VERSION 5.7 ;
  NOWIREEXTENSIONATPIN ON ;
  DIVIDERCHAR "/" ;
  BUSBITCHARS "[]" ;
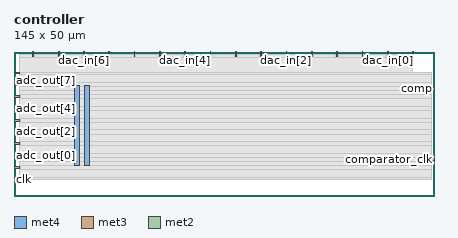
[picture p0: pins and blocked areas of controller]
MACRO controller
  CLASS BLOCK ;
  FOREIGN controller ;
  ORIGIN 0.000 0.000 ;
  SIZE 145.000 BY 50.000 ;
  PIN GND
    DIRECTION INOUT ;
    USE GROUND ;
    PORT
      LAYER met4 ;
        RECT 24.340 10.640 25.940 38.320 ;
    END
  END GND
  PIN VDD
    DIRECTION INOUT ;
    USE POWER ;
    PORT
      LAYER met4 ;
        RECT 21.040 10.640 22.640 38.320 ;
    END
  END VDD
  PIN adc_out[0]
    DIRECTION OUTPUT ;
    USE SIGNAL ;
    ANTENNADIFFAREA 0.445500 ;
    PORT
      LAYER met3 ;
        RECT 0.000 13.640 2.000 14.240 ;
    END
  END adc_out[0]
  PIN adc_out[1]
    DIRECTION OUTPUT ;
    USE SIGNAL ;
    ANTENNADIFFAREA 0.445500 ;
    PORT
      LAYER met3 ;
        RECT 0.000 17.720 2.000 18.320 ;
    END
  END adc_out[1]
  PIN adc_out[2]
    DIRECTION OUTPUT ;
    USE SIGNAL ;
    ANTENNADIFFAREA 0.445500 ;
    PORT
      LAYER met3 ;
        RECT 0.000 21.800 2.000 22.400 ;
    END
  END adc_out[2]
  PIN adc_out[3]
    DIRECTION OUTPUT ;
    USE SIGNAL ;
    ANTENNADIFFAREA 0.445500 ;
    PORT
      LAYER met3 ;
        RECT 0.000 25.880 2.000 26.480 ;
    END
  END adc_out[3]
  PIN adc_out[4]
    DIRECTION OUTPUT ;
    USE SIGNAL ;
    ANTENNADIFFAREA 0.445500 ;
    PORT
      LAYER met3 ;
        RECT 0.000 29.960 2.000 30.560 ;
    END
  END adc_out[4]
  PIN adc_out[5]
    DIRECTION OUTPUT ;
    USE SIGNAL ;
    ANTENNADIFFAREA 0.445500 ;
    PORT
      LAYER met3 ;
        RECT 0.000 34.040 2.000 34.640 ;
    END
  END adc_out[5]
  PIN adc_out[6]
    DIRECTION OUTPUT ;
    USE SIGNAL ;
    ANTENNADIFFAREA 0.445500 ;
    PORT
      LAYER met3 ;
        RECT 0.000 38.120 2.000 38.720 ;
    END
  END adc_out[6]
  PIN adc_out[7]
    DIRECTION OUTPUT ;
    USE SIGNAL ;
    ANTENNADIFFAREA 0.445500 ;
    PORT
      LAYER met3 ;
        RECT 0.000 42.200 2.000 42.800 ;
    END
  END adc_out[7]
  PIN clk
    DIRECTION INPUT ;
    USE SIGNAL ;
    ANTENNAGATEAREA 0.852000 ;
    PORT
      LAYER met3 ;
        RECT 0.000 5.480 2.000 6.080 ;
    END
  END clk
  PIN comp
    DIRECTION INPUT ;
    USE SIGNAL ;
    ANTENNAGATEAREA 0.196500 ;
    PORT
      LAYER met3 ;
        RECT 143.000 36.760 145.000 37.360 ;
    END
  END comp
  PIN comparator_clk
    DIRECTION OUTPUT ;
    USE SIGNAL ;
    ANTENNADIFFAREA 0.445500 ;
    PORT
      LAYER met3 ;
        RECT 143.000 12.280 145.000 12.880 ;
    END
  END comparator_clk
  PIN dac_in[0]
    DIRECTION OUTPUT ;
    USE SIGNAL ;
    ANTENNADIFFAREA 0.445500 ;
    PORT
      LAYER met2 ;
        RECT 128.890 48.000 129.170 50.000 ;
    END
  END dac_in[0]
  PIN dac_in[1]
    DIRECTION OUTPUT ;
    USE SIGNAL ;
    ANTENNADIFFAREA 0.445500 ;
    PORT
      LAYER met2 ;
        RECT 111.410 48.000 111.690 50.000 ;
    END
  END dac_in[1]
  PIN dac_in[2]
    DIRECTION OUTPUT ;
    USE SIGNAL ;
    ANTENNADIFFAREA 0.445500 ;
    PORT
      LAYER met2 ;
        RECT 93.930 48.000 94.210 50.000 ;
    END
  END dac_in[2]
  PIN dac_in[3]
    DIRECTION OUTPUT ;
    USE SIGNAL ;
    ANTENNADIFFAREA 0.445500 ;
    PORT
      LAYER met2 ;
        RECT 76.450 48.000 76.730 50.000 ;
    END
  END dac_in[3]
  PIN dac_in[4]
    DIRECTION OUTPUT ;
    USE SIGNAL ;
    ANTENNADIFFAREA 0.445500 ;
    PORT
      LAYER met2 ;
        RECT 58.970 48.000 59.250 50.000 ;
    END
  END dac_in[4]
  PIN dac_in[5]
    DIRECTION OUTPUT ;
    USE SIGNAL ;
    ANTENNADIFFAREA 0.445500 ;
    PORT
      LAYER met2 ;
        RECT 41.490 48.000 41.770 50.000 ;
    END
  END dac_in[5]
  PIN dac_in[6]
    DIRECTION OUTPUT ;
    USE SIGNAL ;
    ANTENNADIFFAREA 0.445500 ;
    PORT
      LAYER met2 ;
        RECT 24.010 48.000 24.290 50.000 ;
    END
  END dac_in[6]
  PIN dac_in[7]
    DIRECTION OUTPUT ;
    USE SIGNAL ;
    ANTENNADIFFAREA 0.445500 ;
    PORT
      LAYER met2 ;
        RECT 6.530 48.000 6.810 50.000 ;
    END
  END dac_in[7]
  PIN dac_in_n[0]
    DIRECTION OUTPUT ;
    USE SIGNAL ;
    ANTENNADIFFAREA 0.445500 ;
    PORT
      LAYER met2 ;
        RECT 137.630 48.000 137.910 50.000 ;
    END
  END dac_in_n[0]
  PIN dac_in_n[1]
    DIRECTION OUTPUT ;
    USE SIGNAL ;
    ANTENNADIFFAREA 0.445500 ;
    PORT
      LAYER met2 ;
        RECT 120.150 48.000 120.430 50.000 ;
    END
  END dac_in_n[1]
  PIN dac_in_n[2]
    DIRECTION OUTPUT ;
    USE SIGNAL ;
    ANTENNADIFFAREA 0.445500 ;
    PORT
      LAYER met2 ;
        RECT 102.670 48.000 102.950 50.000 ;
    END
  END dac_in_n[2]
  PIN dac_in_n[3]
    DIRECTION OUTPUT ;
    USE SIGNAL ;
    ANTENNADIFFAREA 0.445500 ;
    PORT
      LAYER met2 ;
        RECT 85.190 48.000 85.470 50.000 ;
    END
  END dac_in_n[3]
  PIN dac_in_n[4]
    DIRECTION OUTPUT ;
    USE SIGNAL ;
    ANTENNADIFFAREA 0.445500 ;
    PORT
      LAYER met2 ;
        RECT 67.710 48.000 67.990 50.000 ;
    END
  END dac_in_n[4]
  PIN dac_in_n[5]
    DIRECTION OUTPUT ;
    USE SIGNAL ;
    ANTENNADIFFAREA 0.445500 ;
    PORT
      LAYER met2 ;
        RECT 50.230 48.000 50.510 50.000 ;
    END
  END dac_in_n[5]
  PIN dac_in_n[6]
    DIRECTION OUTPUT ;
    USE SIGNAL ;
    ANTENNADIFFAREA 0.445500 ;
    PORT
      LAYER met2 ;
        RECT 32.750 48.000 33.030 50.000 ;
    END
  END dac_in_n[6]
  PIN dac_in_n[7]
    DIRECTION OUTPUT ;
    USE SIGNAL ;
    ANTENNADIFFAREA 0.445500 ;
    PORT
      LAYER met2 ;
        RECT 15.270 48.000 15.550 50.000 ;
    END
  END dac_in_n[7]
  PIN rst_n
    DIRECTION INPUT ;
    USE SIGNAL ;
    ANTENNAGATEAREA 0.196500 ;
    PORT
      LAYER met3 ;
        RECT 0.000 9.560 2.000 10.160 ;
    END
  END rst_n
  OBS
      LAYER nwell ;
        RECT 5.330 10.795 139.570 38.165 ;
      LAYER li1 ;
        RECT 5.520 10.795 139.380 38.165 ;
      LAYER met1 ;
        RECT 1.910 10.640 139.380 38.320 ;
      LAYER met2 ;
        RECT 1.930 47.720 6.250 48.690 ;
        RECT 7.090 47.720 14.990 48.690 ;
        RECT 15.830 47.720 23.730 48.690 ;
        RECT 24.570 47.720 32.470 48.690 ;
        RECT 33.310 47.720 41.210 48.690 ;
        RECT 42.050 47.720 49.950 48.690 ;
        RECT 50.790 47.720 58.690 48.690 ;
        RECT 59.530 47.720 67.430 48.690 ;
        RECT 68.270 47.720 76.170 48.690 ;
        RECT 77.010 47.720 84.910 48.690 ;
        RECT 85.750 47.720 93.650 48.690 ;
        RECT 94.490 47.720 102.390 48.690 ;
        RECT 103.230 47.720 111.130 48.690 ;
        RECT 111.970 47.720 119.870 48.690 ;
        RECT 120.710 47.720 128.610 48.690 ;
        RECT 129.450 47.720 137.350 48.690 ;
        RECT 1.930 5.595 137.630 47.720 ;
      LAYER met3 ;
        RECT 2.400 41.800 144.130 42.665 ;
        RECT 2.000 39.120 144.130 41.800 ;
        RECT 2.400 37.760 144.130 39.120 ;
        RECT 2.400 37.720 142.600 37.760 ;
        RECT 2.000 36.360 142.600 37.720 ;
        RECT 2.000 35.040 144.130 36.360 ;
        RECT 2.400 33.640 144.130 35.040 ;
        RECT 2.000 30.960 144.130 33.640 ;
        RECT 2.400 29.560 144.130 30.960 ;
        RECT 2.000 26.880 144.130 29.560 ;
        RECT 2.400 25.480 144.130 26.880 ;
        RECT 2.000 22.800 144.130 25.480 ;
        RECT 2.400 21.400 144.130 22.800 ;
        RECT 2.000 18.720 144.130 21.400 ;
        RECT 2.400 17.320 144.130 18.720 ;
        RECT 2.000 14.640 144.130 17.320 ;
        RECT 2.400 13.280 144.130 14.640 ;
        RECT 2.400 13.240 142.600 13.280 ;
        RECT 2.000 11.880 142.600 13.240 ;
        RECT 2.000 10.560 144.130 11.880 ;
        RECT 2.400 9.160 144.130 10.560 ;
        RECT 2.000 6.480 144.130 9.160 ;
        RECT 2.400 5.615 144.130 6.480 ;
  END
END controller
END LIBRARY

